VERSION 5.7 ;
NOWIREEXTENSIONATPIN ON ;
DIVIDERCHAR "/" ;
BUSBITCHARS "[]" ;
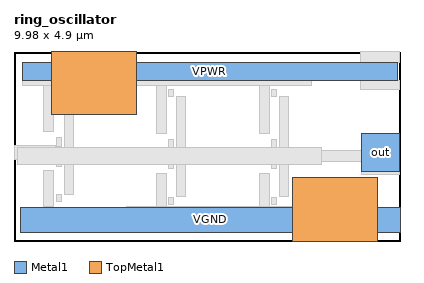
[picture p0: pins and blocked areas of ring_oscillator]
MACRO ring_oscillator
  CLASS BLOCK ;
  FOREIGN ring_oscillator 0.000 0.000 ;
  ORIGIN 0.000 0.000 ;
  SIZE 9.980 BY 4.900 ;
  PIN out
    DIRECTION OUTPUT ;
    USE SIGNAL ;
    PORT
      LAYER Metal1 ;
        RECT 8.950 1.780 9.950 2.780 ;
    END
  END out
  PIN VPWR
    DIRECTION INOUT ;
    USE POWER ;
    PORT
      LAYER Metal1 ;
        RECT 0.210 4.150 9.890 4.600 ;
      LAYER TopMetal1 ;
        RECT 0.970 3.260 3.170 4.900 ;
    END
  END VPWR
  PIN VGND
    DIRECTION INOUT ;
    USE GROUND ;
    PORT
      LAYER Metal1 ;
        RECT 0.160 0.230 9.960 0.860 ;
      LAYER TopMetal1 ;
        RECT 7.170 0.000 9.370 1.640 ;
    END
  END VGND
  OBS
      LAYER GatPoly ;
        RECT 1.090 3.795 1.220 3.975 ;
        RECT 3.990 3.735 4.120 3.915 ;
        RECT 6.650 3.735 6.780 3.915 ;
        RECT 1.090 2.450 1.220 2.675 ;
        RECT 0.750 2.120 1.220 2.450 ;
        RECT 3.990 2.390 4.120 2.615 ;
        RECT 6.650 2.390 6.780 2.615 ;
        RECT 1.090 1.930 1.220 2.120 ;
        RECT 3.650 2.060 4.120 2.390 ;
        RECT 6.310 2.060 6.780 2.390 ;
        RECT 3.990 1.870 4.120 2.060 ;
        RECT 6.650 1.870 6.780 2.060 ;
        RECT 1.090 1.010 1.220 1.190 ;
        RECT 3.990 0.950 4.120 1.130 ;
        RECT 6.650 0.950 6.780 1.130 ;
      LAYER Metal1 ;
        RECT 8.940 4.600 9.940 4.900 ;
        RECT 0.210 4.020 7.670 4.130 ;
        RECT 0.770 2.835 1.030 4.020 ;
        RECT 0.000 2.100 1.080 2.460 ;
        RECT 1.295 2.420 1.525 3.775 ;
        RECT 3.670 2.775 3.930 4.020 ;
        RECT 4.195 2.420 4.425 3.715 ;
        RECT 6.330 2.775 6.590 4.020 ;
        RECT 8.940 3.900 9.940 4.130 ;
        RECT 1.295 2.390 3.950 2.420 ;
        RECT 4.195 2.390 6.620 2.420 ;
        RECT 1.295 2.090 3.965 2.390 ;
        RECT 0.770 0.890 1.030 1.810 ;
        RECT 1.295 1.210 1.525 2.090 ;
        RECT 3.650 2.060 3.965 2.090 ;
        RECT 4.195 2.060 6.625 2.390 ;
        RECT 6.855 2.340 7.085 3.715 ;
        RECT 6.855 2.060 8.950 2.340 ;
        RECT 4.195 2.020 6.620 2.060 ;
        RECT 3.670 0.890 3.930 1.750 ;
        RECT 4.195 1.150 4.425 2.020 ;
        RECT 6.330 0.890 6.590 1.750 ;
        RECT 6.855 1.150 7.085 2.060 ;
        RECT 8.950 1.710 9.950 1.780 ;
        RECT 2.900 0.860 7.670 0.890 ;
      LAYER Metal2 ;
        RECT 0.090 1.980 7.930 2.420 ;
  END
END ring_oscillator
END LIBRARY
